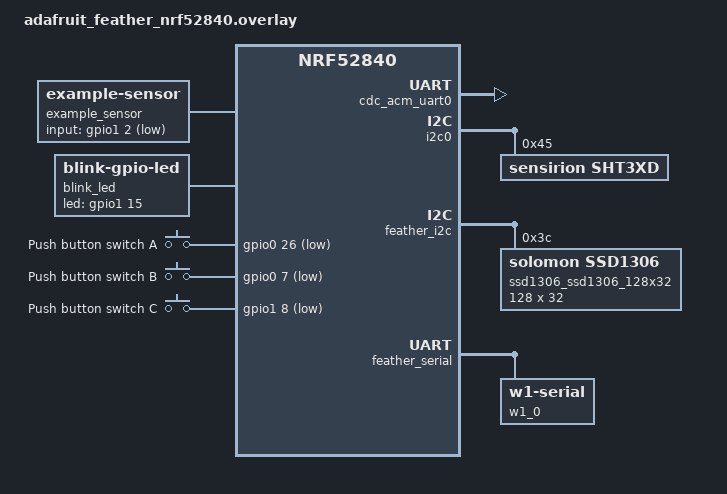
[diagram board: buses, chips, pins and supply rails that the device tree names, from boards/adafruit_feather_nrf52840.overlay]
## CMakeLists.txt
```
#-------------------------------------------------------------------------------
# Zephyr Example Application
#
# Copyright (c) 2021 Nordic Semiconductor ASA
# SPDX-License-Identifier: Apache-2.0

cmake_minimum_required(VERSION 3.13.1)
find_package(Zephyr REQUIRED HINTS $ENV{ZEPHYR_BASE})

list(APPEND ZEPHYR_DTS_PATH ${CMAKE_CURRENT_LIST_DIR/dts})

project(app)
rust_cargo_application()

# Add c-project sources
project(app LANGUAGES C)
#FILE(GLOB app_sources c_src/*.c)
target_sources(app PRIVATE c_src/main.c)
target_sources(app PRIVATE c_src/board_init.c)
target_sources(app PRIVATE c_src/rht_sensor_init.c)
target_sources(app PRIVATE c_src/zbus_bridge.c)
target_sources_ifdef(CONFIG_BT app PRIVATE c_src/smp_ble.c)

target_sources_ifdef(CONFIG_WIFI app PRIVATE c_src/wifi_bridge.c)
target_sources_ifdef(CONFIG_WIFI app PRIVATE c_src/mqtt_bridge.c)

# Checks if 'MQTT_USER' exists in 'wifi_settings.h'
include(CheckSymbolExists)
set(CMAKE_REQUIRED_INCLUDES "${CMAKE_CURRENT_SOURCE_DIR}/../include/app")

check_symbol_exists(MQTT_USER "wifi_settings.h" HAS_MQTT_CREDS)

if(NOT HAS_MQTT_CREDS)
    target_compile_definitions(app PRIVATE MQTT_USER=\"USER\")
    target_compile_definitions(app PRIVATE MQTT_PASSWORD=\"DUMMY\")
endif()
# End MQTT_USER check

set(CMAKE_EXPORT_COMPILE_COMMANDS ON)
```

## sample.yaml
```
# This file is provided so that the application can be compiled using Twister,
# the Zephyr testing tool. In this file, multiple combinations can be specified,
# so that you can easily test all of them locally or in CI.
sample:
  description: RH Sensor application
  name: RH_Sensor_in_Rust 
common:
  build_only: true
  integration_platforms:
    - custom_plank
    - esp32c3_devkitm
    - adafruit_feather_nrf52840
tests:
  app.default: {}
  app.debug:
    extra_overlay_confs:
      - debug.conf
```

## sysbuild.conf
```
# Sysbuild configuration file.

# Enable MCUboot using overwrite only mode for this sample.
SB_CONFIG_BOOTLOADER_MCUBOOT=y

# ECDSA_P256 signature and key
SB_CONFIG_BOOT_SIGNATURE_TYPE_ECDSA_P256=y
SB_CONFIG_BOOT_SIGNATURE_KEY_FILE="${WEST_TOPDIR}/rh_sensor/rh_sensor_key.pem"
```

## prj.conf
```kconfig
# Copyright (c) 2021 Nordic Semiconductor ASA
# SPDX-License-Identifier: Apache-2.0
#
# This file contains selected Kconfig options for the application.

CONFIG_RUST=y
CONFIG_RUST_ALLOC=y

CONFIG_LOG=y
CONFIG_LOG_MODE_MINIMAL=y

#CONFIG_BLINK=y
#CONFIG_BLINK_RUST=y - NOTE: Create the blinky module in rust

# MCU Boot settings (MCUMGR in application, using BLE)
CONFIG_BOOTLOADER_MCUBOOT=y
CONFIG_FLASH=y
CONFIG_FLASH_MAP=y
CONFIG_STREAM_FLASH=y
CONFIG_IMG_MANAGER=y
CONFIG_MCUMGR=y
CONFIG_MCUMGR_GRP_IMG=y
CONFIG_MCUMGR_GRP_IMG_SLOT_INFO=y
CONFIG_MCUMGR_GRP_OS=y
CONFIG_MCUMGR_GRP_OS_INFO=y
CONFIG_MCUMGR_GRP_OS_INFO_BUILD_DATE_TIME=y
CONFIG_MCUMGR_GRP_OS_BOOTLOADER_INFO=y

# Enable the Bluetooth mcumgr transport (unauthenticated).
CONFIG_MCUMGR_TRANSPORT_BT=y
CONFIG_MCUMGR_TRANSPORT_BT_CONN_PARAM_CONTROL=y
CONFIG_MCUMGR_TRANSPORT_NETBUF_SIZE=512

CONFIG_BASE64=y
CONFIG_ZCBOR=y
CONFIG_CRC=y
CONFIG_SERIAL=y
CONFIG_CONSOLE=y

# SHT3x_DIS Sensor Driver
CONFIG_I2C=y
CONFIG_SENSOR=y
CONFIG_SENSOR_LOG_LEVEL_DBG=n
CONFIG_SHT3XD=y
CONFIG_CBPRINTF_FP_SUPPORT=y
CONFIG_SHT3XD_SINGLE_SHOT_MODE=y

# DS18B20 Sensor Driver
CONFIG_W1=y
CONFIG_DS18B20=y

# Example (mock) Sensor Driver
CONFIG_EXAMPLE_SENSOR=y

# Zbus - internal pub-sub bus
CONFIG_ZBUS=y
CONFIG_ZBUS_MSG_SUBSCRIBER=y

# Debug flags:
#CONFIG_DEBUG=y
#CONFIG_DEBUG_COREDUMP=y
#CONFIG_DEBUG_THREAD_INFO=y

# NOTE: Requires percepio to be added in west.yml to work...
#CONFIG_TRACING=y
#CONFIG_PERCEPIO_TRACERECORDER=y
#CONFIG_PERCEPIO_TRC_START_MODE_START=y 
#CONFIG_PERCEPIO_TRC_CFG_STREAM_PORT_RINGBUFFER=y
#CONFIG_PERCEPIO_TRC_CFG_STREAM_PORT_RINGBUFFER_SIZE=16384
```

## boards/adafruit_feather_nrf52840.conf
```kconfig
# Increase stack memory to avoid crashes
CONFIG_MAIN_STACK_SIZE=8192

# Enable USB subsystem - for logging
CONFIG_USB_DEVICE_STACK_NEXT=y
CONFIG_CDC_ACM_SERIAL_INITIALIZE_AT_BOOT=y
CONFIG_USBD_CDC_ACM_LOG_LEVEL_OFF=y

# Enable the Nordic QSPI driver specifically
CONFIG_NORDIC_QSPI_NOR=y
CONFIG_FLASH_PAGE_LAYOUT=y
CONFIG_NORDIC_QSPI_NOR_FLASH_LAYOUT_PAGE_SIZE=4096

# --- Bluetooth LE Core Settings ---
CONFIG_BT=y
CONFIG_BT_PERIPHERAL=y
CONFIG_BT_DEVICE_NAME="RH_Sensor"

# Allow for large Bluetooth data packets.
CONFIG_BT_L2CAP_TX_MTU=498
CONFIG_BT_BUF_ACL_RX_SIZE=502
CONFIG_BT_BUF_ACL_TX_SIZE=502
CONFIG_BT_CTLR_DATA_LENGTH_MAX=251

# Enable Display Drivers
CONFIG_DISPLAY=y
CONFIG_SSD1306=y
CONFIG_HEAP_MEM_POOL_SIZE=2048

# Enable the Character Frame Buffer
CONFIG_CHARACTER_FRAMEBUFFER=y

# Graphics Support
CONFIG_LVGL=y
CONFIG_LV_Z_MEM_POOL_SIZE=16384
CONFIG_LV_Z_VDB_SIZE=64
CONFIG_LV_Z_BITS_PER_PIXEL=1
CONFIG_LV_COLOR_DEPTH_1=y
#CONFIG_LV_Z_COLOR_MONO_HW_INVERSION=y
#CONFIG_LV_Z_SHELL=y
#CONFIG_LV_USE_LOG=y
#CONFIG_LV_LOG_LEVEL_INFO=y
CONFIG_LV_USE_LABEL=y
# CONFIG_LV_USE_ARC=y
# CONFIG_LV_USE_MONKEY=y
# CONFIG_LV_FONT_MONTSERRAT_14=y
```

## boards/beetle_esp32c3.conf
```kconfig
# ESP32C3 Specific Configuration
# -------------------------------

# Wifi settings
#--------------------------------
# Increase stack memory to avoid crashes
CONFIG_MAIN_STACK_SIZE=8192

# --- Bluetooth LE Core Settings ---
CONFIG_BT=y
CONFIG_BT_PERIPHERAL=y
CONFIG_BT_DEVICE_NAME="RH_Sensor"

# Allow for large Bluetooth data packets.
CONFIG_BT_L2CAP_TX_MTU=498
CONFIG_BT_BUF_ACL_RX_SIZE=502
CONFIG_BT_BUF_ACL_TX_SIZE=502
CONFIG_BT_CTLR_DATA_LENGTH_MAX=251

# Enable WiFi
CONFIG_WIFI=y
CONFIG_WIFI_LOG_LEVEL_DBG=n

# Networking config
CONFIG_NETWORKING=y
CONFIG_NET_IPV4=y
CONFIG_NET_TCP=y
CONFIG_POSIX_API=y

# MQTT settings
CONFIG_MQTT_LIB=y
CONFIG_MQTT_LOG_LEVEL_DBG=n

# Get IPv4 address from DHCP
CONFIG_NET_DHCPV4=y

# How long to wait for e.g. DHCP to provide an IP address (seconds)
CONFIG_NET_CONFIG_SETTINGS=n    # Disable auto-configuration...
CONFIG_NET_CONFIG_AUTO_INIT=n   # Disable auto-configuration...

# Network debug config
CONFIG_NET_LOG=n

# Enable Ethernet (required for WiFi)
CONFIG_NET_L2_WIFI_MGMT=y
CONFIG_NET_MGMT=y
CONFIG_NET_MGMT_EVENT=y
CONFIG_NET_MGMT_EVENT_INFO=y
CONFIG_NET_MGMT_EVENT_LOG_LEVEL_DBG=n
#----------------------------------

# Required to get an IP address from DHCP
CONFIG_ESP32_WIFI_STA_AUTO_DHCPV4=y

# Use system heap (instead of runtime) for WiFi
CONFIG_ESP_WIFI_HEAP_SYSTEM=y
CONFIG_HEAP_MEM_POOL_SIZE=84000
```

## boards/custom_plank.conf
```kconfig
CONFIG_USB_DEVICE_STACK_NEXT=y
```

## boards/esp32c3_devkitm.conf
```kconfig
# ESP32C3 Specific Configuration
# -------------------------------

# Wifi settings
#--------------------------------
# Increase stack memory to avoid crashes
CONFIG_MAIN_STACK_SIZE=8192

# Enable WiFi
CONFIG_WIFI=y
CONFIG_WIFI_LOG_LEVEL_DBG=n

# Networking config
CONFIG_NETWORKING=y
CONFIG_NET_IPV4=y
CONFIG_NET_TCP=y
CONFIG_POSIX_API=y

# MQTT settings
CONFIG_MQTT_LIB=y
CONFIG_MQTT_LOG_LEVEL_DBG=n

# Get IPv4 address from DHCP
CONFIG_NET_DHCPV4=y

# How long to wait for e.g. DHCP to provide an IP address (seconds)
CONFIG_NET_CONFIG_SETTINGS=n    # Disable auto-configuration...
CONFIG_NET_CONFIG_AUTO_INIT=n   # Disable auto-configuration...

# Network debug config
CONFIG_NET_LOG=n

# Enable Ethernet (required for WiFi)
CONFIG_NET_L2_WIFI_MGMT=y
CONFIG_NET_MGMT=y
CONFIG_NET_MGMT_EVENT=y
CONFIG_NET_MGMT_EVENT_INFO=y
CONFIG_NET_MGMT_EVENT_LOG_LEVEL_DBG=n
#----------------------------------

# Required to get an IP address from DHCP
CONFIG_ESP32_WIFI_STA_AUTO_DHCPV4=y

# Use system heap (instead of runtime) for WiFi
CONFIG_ESP_WIFI_HEAP_SYSTEM=y
CONFIG_HEAP_MEM_POOL_SIZE=58200
```

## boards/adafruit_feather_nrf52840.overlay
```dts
/*
 * Copyright (c) 2021 Nordic Semiconductor ASA
 *
 * SPDX-License-Identifier: Apache-2.0
 */
#include <adafruit_feather_nrf52840_map.dtsi>

/ {
	/* This uses the same gpio as th user button declared in board file! */
	example_sensor: example-sensor {
		compatible = "zephyr,example-sensor";
		input-gpios = <&gpio1 2 (GPIO_PULL_UP | GPIO_ACTIVE_LOW)>;
	};

	blink_led: blink-led {
		compatible = "blink-gpio-led";
		led-gpios = <&gpio1 15 GPIO_ACTIVE_HIGH>;
		blink-period-ms = <1000>;
	};

	buttons {
		compatible = "gpio-keys";

		buttonA: button_A {
			//gpios = <&feather_header 16 (GPIO_PULL_UP | GPIO_ACTIVE_LOW)>; feather_header can't be mapped into dt-rust.yml... ToDo...?
			gpios = <&gpio0 26 (GPIO_PULL_UP | GPIO_ACTIVE_LOW)>;
			label = "Push button switch A";
		};

		buttonB: button_B {
			//gpios = <&feather_header 15 (GPIO_PULL_UP | GPIO_ACTIVE_LOW)>;
			gpios = <&gpio0 7 (GPIO_PULL_UP | GPIO_ACTIVE_LOW)>;
			label = "Push button switch B";
		};

		buttonC: button_C {
			//gpios = <&feather_header 14 (GPIO_PULL_UP | GPIO_ACTIVE_LOW)>;
			gpios = <&gpio1 8 (GPIO_PULL_UP | GPIO_ACTIVE_LOW)>;
			label = "Push button switch C";
		};
	};

	chosen {
		zephyr,console = &cdc_acm_uart0;
		zephyr,uart-mcumgr = &cdc_acm_uart0;
		zephyr,flash = &flash0;
		zephyr,code-partition = &slot0_partition;
        zephyr,display = &ssd1306_ssd1306_128x32;
	};
	
	aliases {
		userbutton = &buttonB;
	};
};

&zephyr_udc0 {
	cdc_acm_uart0: cdc_acm_uart0 {
		compatible = "zephyr,cdc-acm-uart";
	};
};

&i2c0 { /* SDA P0.12, SCL P0.11, Alert P1.08 */
	status = "okay";
	sht3xd:sht3xd@45 {
		compatible = "sensirion,sht3xd";
		reg = <0x45>; /* ADDR pin pulled high, else 0x44 */
		//alert-gpios = <&gpio1 8 GPIO_ACTIVE_HIGH>; Disable IRQ pin - only used with polling
	};
};

&feather_i2c {
	status = "okay";

	ssd1306_ssd1306_128x32: ssd1306@3c {
		compatible = "solomon,ssd1306";
		reg = <0x3c>;
		width = <128>;
		height = <32>;
		segment-offset = <0>;
		page-offset = <0>;
		display-offset = <0>;
		multiplex-ratio = <31>;
		segment-remap;
		com-invdir;
		com-sequential;
		prechargep = <0x22>;
	};
};

&feather_serial {
	status = "okay";

	w1_0: w1-zephyr-serial-0 {
		compatible = "zephyr,w1-serial";
		status = "okay";

		ds18b20 {
			compatible = "maxim,ds18b20";
			family-code = <0x28>;
			resolution = <12>;
			status = "okay";
		};
	};
};
```

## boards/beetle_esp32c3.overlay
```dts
/*
 * Copyright (c) 2026 Dooleweerdt
 * SPDX-License-Identifier: Apache-2.0
 */

/* This devicetree overlay file will be automatically picked by the Zephyr
 * build system when building the sample for the esp32c3_devkitm board. It shows
 * how the example-application can be built on sample boards already provided
 * by Zephyr.
 */

/ {
	aliases {
		led0 = &blue_led;
		//userbutton = &user_button1;
	};

	example_sensor: example-sensor {
		compatible = "zephyr,example-sensor";
		input-gpios = <&gpio0 7 (GPIO_PULL_UP | GPIO_ACTIVE_LOW)>;
	};

    /* Define the 1-Wire bus at the root level */
    w1: w1 {
        compatible = "zephyr,w1-gpio";
        /* Pick an available GPIO, e.g., GPIO 4 */
        gpios = <&gpio0 4 (GPIO_ACTIVE_HIGH | GPIO_OPEN_DRAIN)>;
        status = "okay";

        ds18b20: ds18b20 {
            compatible = "maxim,ds18b20";
            family-code = <0x28>;
            resolution = <12>;
            status = "okay";
        };
    };

	chosen {
		zephyr,console = &usb_serial;
		zephyr,shell-uart = &usb_serial;
 		zephyr,uart-mcumgr = &usb_serial; 
 	};
};

&i2c0 { /* SDA P8, SCL P9, Alert P1 */
	status = "okay";
	sht3xd:sht3xd@45 {
		compatible = "sensirion,sht3xd";
		reg = <0x45>; /* ADDR pin pulled high, else 0x44 */
		//alert-gpios = <&gpio0 1 GPIO_ACTIVE_HIGH>; - Only used in polling, so remove IRQ pin.
	};
};

&usb_serial {
	status = "okay";
};

&wifi {
    status = "okay";
};
```

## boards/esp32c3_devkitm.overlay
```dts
/*
 * Copyright (c) 2021 Nordic Semiconductor ASA
 * SPDX-License-Identifier: Apache-2.0
 */

/* This devicetree overlay file will be automatically picked by the Zephyr
 * build system when building the sample for the esp32c3_devkitm board. It shows
 * how the example-application can be built on sample boards already provided
 * by Zephyr.
 */

/ {
	aliases {
		led0 = &blue_led;
		userbutton = &user_button1;
	};

	example_sensor: example-sensor {
		compatible = "zephyr,example-sensor";
		input-gpios = <&gpio0 7 (GPIO_PULL_UP | GPIO_ACTIVE_LOW)>;
	};

	leds {
		compatible = "gpio-leds";

		blue_led: led_0 {
			gpios = <&gpio0 10 GPIO_ACTIVE_HIGH>;
			label = "Blue LED";
		};
	};

    /* Define the 1-Wire bus at the root level */
    w1: w1 {
        compatible = "zephyr,w1-gpio";
        /* Pick an available GPIO, e.g., GPIO 4 */
        gpios = <&gpio0 4 (GPIO_ACTIVE_HIGH | GPIO_OPEN_DRAIN)>;
        status = "okay";

        ds18b20: ds18b20 {
            compatible = "maxim,ds18b20";
            family-code = <0x28>;
            resolution = <12>;
            status = "okay";
        };
    };

	chosen {
		zephyr,console = &usb_serial;
		zephyr,shell-uart = &usb_serial;
 		zephyr,uart-mcumgr = &usb_serial; 
 	};
};

&i2c0 { /* SDA P8, SCL P9, Alert P1 */
	status = "okay";
	sht3xd:sht3xd@45 {
		compatible = "sensirion,sht3xd";
		reg = <0x45>; /* ADDR pin pulled high, else 0x44 */
		//alert-gpios = <&gpio0 1 GPIO_ACTIVE_HIGH>; - Only used in polling, so remove IRQ pin.
	};
};

&usb_serial {
	status = "okay";
};

&wifi {
    status = "okay";
};
```

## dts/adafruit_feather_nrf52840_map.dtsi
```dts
/* Expand internal MCUboot and Slot0 partitions */
&flash0 {
    partitions {
        ranges;
        #address-cells = <1>;
        #size-cells = <1>;

		/* Delete the default board partitions that start at 0xc000 and 0x82000 */
        /delete-node/ partition@c000;
        /delete-node/ partition@82000;

        /* 1. MCUboot partition increased to 64KB (0x10000) */
        boot_partition: partition@0 {
            compatible = "zephyr,mapped-partition";
            label = "mcuboot";
            reg = <0x00000000 0x00010000>;
        };

        /* 2. Slot 0 starts at 0x10000 and uses remaining internal flash */
        slot0_partition: partition@10000 {
            compatible = "zephyr,mapped-partition";
            label = "image-0";
            reg = <0x00010000 0x000E8000>;
        };

        /* 3. Storage partition from 0xF8000 -> 0xFFFFF */
    };
};

&gd25q16 {
    status = "okay";
    partitions {
        compatible = "fixed-partitions";
        #address-cells = <1>;
        #size-cells = <1>;

        /* MCUboot secondary slot - One page larger than slot0 (swap page) */
        slot1_partition: partition@0 {
            label = "image-1";
            reg = <0x00000000 0x000E9000>;
        };

        /* Rest of the 16Mbit (2MB) Flash */
        ext_storage_partition: partition@E9000 {
            label = "ext_storage";
            reg = <0x000E9000 0x00117000>;
        };
    };
};
```

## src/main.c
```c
/*
 * Copyright (c) 2021 Nordic Semiconductor ASA
 * SPDX-License-Identifier: Apache-2.0
 */

#include <zephyr/kernel.h>
#include <zephyr/drivers/sensor.h>
#include <zephyr/logging/log.h>

#include <app/drivers/blink.h>

#include <app_version.h>

// Custom libraries
#include <app/drivers/wifi.h>
#include <app/wifi_settings.h>

LOG_MODULE_REGISTER(main, CONFIG_APP_LOG_LEVEL);

#define BLINK_PERIOD_MS_STEP 100U
#define BLINK_PERIOD_MS_MAX  1000U

int main(void)
{
	int ret;
	const struct device *sensor;
    #if CONFIG_BLINK
    const struct device *blink;
    #endif
	struct sensor_value val;

	printk("Zephyr - RH Sensor in Rust %s\n", STRINGIFY(APP_BUILD_VERSION));

	sensor = DEVICE_DT_GET(DT_NODELABEL(example_sensor));
	if (!device_is_ready(sensor)) {
		LOG_ERR("Sensor not ready");
		return 0;
	}

    #if CONFIG_BLINK
	blink = DEVICE_DT_GET(DT_NODELABEL(blink_led));
	if (!device_is_ready(blink)) {
		LOG_ERR("Blink LED not ready");
		return 0;
	}

	ret = blink_off(blink);
	if (ret < 0) {
		LOG_ERR("Could not turn off LED (%d)", ret);
		return 0;
	}
    #endif

	printk("Use the sensor to change LED blinking period\n");

    #if CONFIG_WIFI
    #if WIFI_CREDENTIALS
    // Wifi initialization - Test code
    wifi_init();

    do {
        // Connect to the WiFi network (blocking)
        ret = wifi_connect(WIFI_SSID, WIFI_PSK);
        if (ret < 0) {
            printk("Error (%d): WiFi connection failed. Retrying in 5s...\r\n", ret);
            k_sleep(K_MSEC(5000)); // Wait before retrying
        }
    } while (ret < 0);

    // Wait to receive an IP address (blocking)
    wifi_wait_for_ip_addr();

    // Wifi initialization - Test code End
    #else
    #error "WIFI_SSID is not defined. Please define WIFI_SSID and WIFI"
    #endif // WIFI_SSID
    #endif

	while (1) {
		ret = sensor_sample_fetch(sensor);
		if (ret < 0) {
			LOG_ERR("Could not fetch sample (%d)", ret);
			return 0;
		}

		ret = sensor_channel_get(sensor, SENSOR_CHAN_AMBIENT_TEMP, &val);
		if (ret < 0) {
			LOG_ERR("Could not get sample (%d)", ret);
			return 0;
		}

        printk("Temperature: %d.%06d C\n", val.val1, val.val2);

		k_sleep(K_MSEC(1000));
	}

	return 0;
}

/* Wifi code from Shawn Hymel (DigiKey): https://www.digikey.dk/da/maker/tutorials/2025/introduction-to-zephyr-part-11-wifi-and-iot

#include <stdio.h>
#include <string.h>
#include <zephyr/kernel.h>
#include <zephyr/net/socket.h>

// Custom libraries
#include "wifi.h"

// WiFi settings
#define WIFI_SSID "MySSID"
#define WIFI_PSK "MyPassword"

// HTTP GET settings
#define HTTP_HOST "example.com"
#define HTTP_URL "/"

// Globals
static char response[512];

// Print the results of a DNS lookup
void print_addrinfo(struct zsock_addrinfo **results)
{
    char ipv4[INET_ADDRSTRLEN];
    char ipv6[INET6_ADDRSTRLEN];
    struct sockaddr_in *sa;
    struct sockaddr_in6 *sa6;
    struct zsock_addrinfo *rp;

    // Iterate through the results
    for (rp = *results; rp != NULL; rp = rp->ai_next) {

        // Print IPv4 address
        if (rp->ai_addr->sa_family == AF_INET) {
            sa = (struct sockaddr_in *)rp->ai_addr;
            zsock_inet_ntop(AF_INET, &sa->sin_addr, ipv4, INET_ADDRSTRLEN);
            printk("IPv4: %s\r\n", ipv4);
        }

        // Print IPv6 address
        if (rp->ai_addr->sa_family == AF_INET6) {
            sa6 = (struct sockaddr_in6 *)rp->ai_addr;
            zsock_inet_ntop(AF_INET6, &sa6->sin6_addr, ipv6, INET6_ADDRSTRLEN);
            printk("IPv6: %s\r\n", ipv6);
        }
    }
}

int main(void)
{
    struct zsock_addrinfo hints;
    struct zsock_addrinfo *res;
    char http_request[512];
    int sock;
    int len;
    uint32_t rx_total;
    int ret;

    printk("HTTP GET Demo\r\n");

    // Initialize WiFi
    wifi_init();

    // Connect to the WiFi network (blocking)
    ret = wifi_connect(WIFI_SSID, WIFI_PSK);
    if (ret < 0) {
        printk("Error (%d): WiFi connection failed\r\n", ret);
        return 0;
    }

    // Wait to receive an IP address (blocking)
    wifi_wait_for_ip_addr();

    // Construct HTTP GET request
    snprintf(http_request,
             sizeof(http_request),
             "GET %s HTTP/1.1\r\nHost: %s\r\n\r\n",
             HTTP_URL,
             HTTP_HOST);

    // Clear and set address info
    memset(&hints, 0, sizeof(hints));
    hints.ai_family = AF_INET;              // IPv4
    hints.ai_socktype = SOCK_STREAM;        // TCP socket

    // Perform DNS lookup
    printk("Performing DNS lookup...\r\n");
    ret = zsock_getaddrinfo(HTTP_HOST, "80", &hints, &res);
    if (ret != 0) {
        printk("Error (%d): Could not perform DNS lookup\r\n", ret);
        return 0;
    }

    // Print the results of the DNS lookup
    print_addrinfo(&res);

    // Create a new socket
    sock = zsock_socket(res->ai_family, res->ai_socktype, res->ai_protocol);
    if (sock < 0) {
        printk("Error (%d): Could not create socket\r\n", errno);
        return 0;
    }

    // Connect the socket
    ret = zsock_connect(sock, res->ai_addr, res->ai_addrlen);
    if (ret < 0) {
        printk("Error (%d): Could not connect the socket\r\n", errno);
        return 0;
    }

    // Set the request
    printk("Sending HTTP request...\r\n");
    ret = zsock_send(sock, http_request, strlen(http_request), 0);
    if (ret < 0) {
        printk("Error (%d): Could not send request\r\n", errno);
        return 0;
    }

    // Print the response
    printk("Response:\r\n\r\n");
    rx_total = 0;
    while (1) {

        // Receive data from the socket
        len = zsock_recv(sock, response, sizeof(response) - 1, 0);

        // Check for errors
        if (len < 0) {
            printk("Receive error (%d): %s\r\n", errno, strerror(errno));
            return 0;
        }

        // Check for end of data
        if (len == 0) {
            break;
        }

        // Null-terminate the response string and print it
        response[len] = '\0';
        printk("%s", response);
        rx_total += len;
    }

    // Print the total number of bytes received
    printk("\r\nTotal bytes received: %u\r\n", rx_total);

    // Close the socket
    zsock_close(sock);

    return 0;
}
*/
```

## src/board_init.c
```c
/*
 * Copyright (c) 2021 Nordic Semiconductor ASA
 * SPDX-License-Identifier: Apache-2.0
 */

#include <zephyr/init.h>
#include <zephyr/logging/log.h>
#include <zephyr/drivers/display.h>
#include <zephyr/display/cfb.h>

#include <app_version.h>

// Custom libraries
#include <app/drivers/wifi.h>
#include <app/wifi_settings.h>

LOG_MODULE_REGISTER(board_init, CONFIG_APP_LOG_LEVEL);

#ifndef WIFI_CREDENTIALS
// Pseudo credentials for testing - real credentials is in wifi_settings.h
#define WIFI_CREDENTIALS 1
#define WIFI_SSID "WirelessNetwork"
#define WIFI_PSK "Password"
#endif

#if CONFIG_DISPLAY
#define DISPLAY_DRIVER      DT_CHOSEN(zephyr_display)
const struct device *display_dev = DEVICE_DT_GET(DISPLAY_DRIVER);

#if CONFIG_LVGL
#include <lvgl.h>
//LV_IMG_DECLARE(gemini-icon);
//LV_IMG_DECLARE(zephyr-icon);
#endif // CONFIG_LVGL

#endif // CONFIG_DISPLAY

int board_init(void)
{
    printk("Zephyr - RH Sensor in Rust %s\n", STRINGIFY(APP_BUILD_VERSION));

    #if CONFIG_DISPLAY
    if (!device_is_ready(display_dev)) {
        // Handle error
        return ENODEV;
    }

    // Now you can use display_blanking_off(display_dev) 
    // and start writing pixels or text.
    int ret = display_blanking_off(display_dev);
	if (ret < 0 && ret != -ENOSYS) {
		LOG_ERR("Failed to turn blanking off (error %d)", ret);
    }

    #if CONFIG_LVGL
    lv_obj_t * label1 = lv_label_create(lv_scr_act());
    lv_label_set_text(label1, "Zephyr LVGL!");
    lv_obj_align(label1, LV_ALIGN_TOP_LEFT, 0, 0);
    lv_timer_handler();
    #else
    // Initialize the CFB (Character Frame Buffer)
    if (cfb_framebuffer_init(display_dev)) {
        return EIO; // Error initializing framebuffer
    }

    // Clear the screen and set font
    cfb_framebuffer_clear(display_dev, true);

    // Print text at coordinates (x, y)
    cfb_print(display_dev, "Zephyr RTOS!", 0, 0);
    cfb_print(display_dev, "Feather nRF52840", 0, 16);

    // Finalize and push the buffer to the hardware
    cfb_framebuffer_finalize(display_dev);
    #endif // CONFIG_LVGL
    #endif // CONFIG_DISPLAY

    #if CONFIG_WIFI
    #if WIFI_CREDENTIALS
	int ret;

    // Wifi initialization - Test code
    wifi_init();

    do {
        // Connect to the WiFi network (blocking)
        ret = wifi_connect(WIFI_SSID, WIFI_PSK);
        if (ret < 0) {
            printk("Error (%d): WiFi connection failed. Retrying in 5s...\r\n", ret);
            k_sleep(K_MSEC(5000)); // Wait before retrying
        }
    } while (ret < 0);

    // Wait to receive an IP address (blocking)
    wifi_wait_for_ip_addr();

    // Wifi initialization - Test code End
    #else
    #error "WIFI_SSID is not defined. Please define WIFI_SSID and WIFI"
    #endif // WIFI_SSID
    #endif

    return 0;
}

SYS_INIT_NAMED(board_init, &board_init, APPLICATION, 256);
```

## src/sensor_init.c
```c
#include <zephyr/device.h>
#include <zephyr/drivers/sensor.h>
#include <zephyr/logging/log.h>

LOG_MODULE_REGISTER(sensor_init, CONFIG_APP_LOG_LEVEL);

const struct device * is_sensor_ready(void)
{
    static const struct device *sensor;

    sensor = DEVICE_DT_GET(DT_NODELABEL(sht3xd));
	if (!device_is_ready(sensor)) {
		LOG_ERR("SHT3x sensor is not ready");
        sensor = NULL;
	}

    if (sensor == NULL) {
        sensor = DEVICE_DT_GET(DT_NODELABEL(example_sensor));
        if (!device_is_ready(sensor)) {
            LOG_ERR("Example sensor is not ready");
            sensor = NULL;
        }
    }

    LOG_INF("Sensor device: %s", sensor->name);

    if (sensor == NULL) {
        return NULL;
    }
	return sensor;
}
```

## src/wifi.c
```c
#include <string.h>
#include <zephyr/kernel.h>
#include <zephyr/net/wifi_mgmt.h>

// Wifi code from Shawn Hymel (DigiKey): https://www.digikey.dk/da/maker/tutorials/2025/introduction-to-zephyr-part-11-wifi-and-iot 

// Event callbacks
static struct net_mgmt_event_callback wifi_cb;
static struct net_mgmt_event_callback ipv4_cb;

// Semaphores
static K_SEM_DEFINE(sem_wifi, 0, 1);
static K_SEM_DEFINE(sem_ipv4, 0, 1);

// Called when the WiFi is connected
static void on_wifi_connection_event(struct net_mgmt_event_callback *cb,
                                     uint64_t mgmt_event,
                                     struct net_if *iface)
{
    const struct wifi_status *status = (const struct wifi_status *)cb->info;

    if (mgmt_event == NET_EVENT_WIFI_CONNECT_RESULT) {
        if (status->status) {
            printk("Error (%d): Connection request failed\r\n", status->status);
        } else {
            printk("Connected!\r\n");
            k_sem_give(&sem_wifi);
        }
    } else if (mgmt_event == NET_EVENT_WIFI_DISCONNECT_RESULT) {
        if (status->status) {
            printk("Error (%d): Disconnection request failed\r\n", status->status);
        } else {
            printk("Disconnected\r\n");
            k_sem_take(&sem_wifi, K_NO_WAIT);
        }
    }
}

// Event handler for WiFi management events
static void on_ipv4_obtained(struct net_mgmt_event_callback *cb,
                             uint64_t mgmt_event,
                             struct net_if *iface)
{
    // Signal that the IP address has been obtained
    if (mgmt_event == NET_EVENT_IPV4_ADDR_ADD) {
        k_sem_give(&sem_ipv4);
    }
}

// Initialize the WiFi event callbacks
void wifi_init(void)
{
    // Initialize the event callbacks
    net_mgmt_init_event_callback(&wifi_cb,
                                 on_wifi_connection_event,
                                 NET_EVENT_WIFI_CONNECT_RESULT | NET_EVENT_WIFI_DISCONNECT_RESULT);
    net_mgmt_init_event_callback(&ipv4_cb,
                                 on_ipv4_obtained,
                                 NET_EVENT_IPV4_ADDR_ADD);
    
    // Add the event callbacks
    net_mgmt_add_event_callback(&wifi_cb);
    net_mgmt_add_event_callback(&ipv4_cb);
}

// Connect to the WiFi network (blocking)
int wifi_connect(char *ssid, char *psk)
{
    int ret;
    struct net_if *iface;
    struct wifi_connect_req_params params;

    // Get the default networking interface
    iface = net_if_get_default();

    // Fill in the connection request parameters
    params.ssid = (const uint8_t *)ssid;
    params.ssid_length = strlen(ssid);
    params.psk = (const uint8_t *)psk;
    params.psk_length = strlen(psk);
    params.security = WIFI_SECURITY_TYPE_PSK;
    params.band = WIFI_FREQ_BAND_UNKNOWN;
    params.channel = WIFI_CHANNEL_ANY;
    params.mfp = WIFI_MFP_OPTIONAL;

    // Connect to the WiFi network
    ret = net_mgmt(NET_REQUEST_WIFI_CONNECT,
                   iface,
                   &params,
                   sizeof(params));

    // Wait for the connection to complete
    k_sem_take(&sem_wifi, K_FOREVER);

    return ret;
}

// Wait for IP address (blocking)
void wifi_wait_for_ip_addr(void)
{
    struct wifi_iface_status status;
    struct net_if *iface;
    char ip_addr[NET_IPV4_ADDR_LEN];
    char gw_addr[NET_IPV4_ADDR_LEN];

    // Get interface
    iface = net_if_get_default();

    // Wait for the IPv4 address to be obtained
    k_sem_take(&sem_ipv4, K_FOREVER);

    // Get the WiFi status
    if (net_mgmt(NET_REQUEST_WIFI_IFACE_STATUS,
                 iface,
                 &status,
                 sizeof(struct wifi_iface_status))) {
        printk("Error: WiFi status request failed\r\n");
    }

    // Get the IP address
    memset(ip_addr, 0, sizeof(ip_addr));
    if (net_addr_ntop(AF_INET,
                      &iface->config.ip.ipv4->unicast[0].ipv4.address.in_addr,
                      ip_addr,
                      sizeof(ip_addr)) == NULL) {
        printk("Error: Could not convert IP address to string\r\n");
    }

    // Get the gateway address
    memset(gw_addr, 0, sizeof(gw_addr));
    if (net_addr_ntop(AF_INET,
                      &iface->config.ip.ipv4->gw,
                      gw_addr,
                      sizeof(gw_addr)) == NULL) {
        printk("Error: Could not convert gateway address to string\r\n");
    }

    // Print the WiFi status
    printk("WiFi status:\r\n");
    if (status.state >= WIFI_STATE_ASSOCIATED) {
        printk("  SSID: %-32s\r\n", status.ssid);
        printk("  Band: %s\r\n", wifi_band_txt(status.band));
        printk("  Channel: %d\r\n", status.channel);
        printk("  Security: %s\r\n", wifi_security_txt(status.security));
        printk("  IP address: %s\r\n", ip_addr);
        printk("  Gateway: %s\r\n", gw_addr);
    }
}

// Disconnect from the WiFi network
int wifi_disconnect(void)
{
    int ret;
    struct net_if *iface = net_if_get_default();

    ret = net_mgmt(NET_REQUEST_WIFI_DISCONNECT, iface, NULL, 0);

    return ret;
}
```
